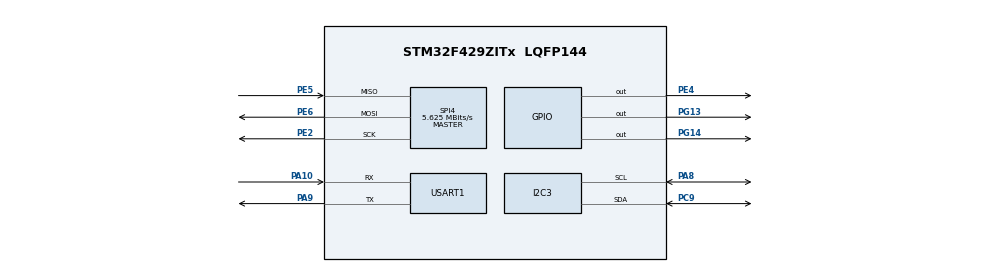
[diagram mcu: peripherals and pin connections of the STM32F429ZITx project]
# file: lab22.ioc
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I2C3.I2C_Mode=I2C_Fast
Mcu.Family=STM32F4
Mcu.Name=STM32F429ZITx
Mcu.Package=LQFP144
NVIC.PriorityGroup=NVIC_PRIORITYGROUP_4
PA10.Mode=Asynchronous
PA10.Signal=USART1_RX
PA8.Mode=I2C
PA8.Signal=I2C3_SCL
PA9.Mode=Asynchronous
PA9.Signal=USART1_TX
PC9.Mode=I2C
PC9.Signal=I2C3_SDA
PE2.Mode=Full_Duplex_Master
PE2.Signal=SPI4_SCK
PE4.Signal=GPIO_Output
PE5.Mode=Full_Duplex_Master
PE5.Signal=SPI4_MISO
PE6.Mode=Full_Duplex_Master
PE6.Signal=SPI4_MOSI
PG13.Signal=GPIO_Output
PG14.Signal=GPIO_Output
PH0/OSC_IN.Mode=HSE-External-Oscillator
PH0/OSC_IN.Signal=RCC_OSC_IN
PH1/OSC_OUT.Mode=HSE-External-Oscillator
PH1/OSC_OUT.Signal=RCC_OSC_OUT
ProjectManager.HeapSize=0x200
ProjectManager.StackSize=0x400
ProjectManager.TargetToolchain=STM32CubeIDE
RCC.48MHZClocksFreq_Value=90000000
RCC.AHBFreq_Value=180000000
RCC.APB1CLKDivider=RCC_HCLK_DIV4
RCC.APB1Freq_Value=45000000
RCC.APB1TimFreq_Value=90000000
RCC.APB2CLKDivider=RCC_HCLK_DIV2
RCC.APB2Freq_Value=90000000
RCC.APB2TimFreq_Value=180000000
RCC.CortexFreq_Value=180000000
RCC.HCLKFreq_Value=180000000
RCC.HSE_VALUE=25000000
RCC.HSI_VALUE=16000000
RCC.LSE_VALUE=32768
RCC.PLLM=15
RCC.PLLN=216
RCC.PLLSourceVirtual=RCC_PLLSOURCE_HSE
RCC.SYSCLKFreq_VALUE=180000000
RCC.SYSCLKSource=RCC_SYSCLKSOURCE_PLLCLK
RCC.VCOOutputFreq_Value=360000000
SPI4.BaudRatePrescaler=SPI_BAUDRATEPRESCALER_16
SPI4.CalculateBaudRate=5.625 MBits/s
SPI4.Direction=SPI_DIRECTION_2LINES
SPI4.Mode=SPI_MODE_MASTER
SPI4.VirtualType=VM_MASTER
USART1.VirtualMode=VM_ASYNC
board=custom

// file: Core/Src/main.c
/* USER CODE BEGIN Header */
/**
 ******************************************************************************
 * @file           : main.c
 * @brief          : Main program body
 ******************************************************************************
 * @attention
 *
 * Copyright (c) 2025 STMicroelectronics.
 * All rights reserved.
 *
 * This software is licensed under terms that can be found in the LICENSE file
 * in the root directory of this software component.
 * If no LICENSE file comes with this software, it is provided AS-IS.
 *
 ******************************************************************************
 */
/* USER CODE END Header */
#include "main.h"

/* USER CODE BEGIN Includes */
#include "tm_stm32f4_mfrc522.h"
#include "stdio.h"
#include "string.h"
#include "SH1106.h"
#include "fonts.h"
/* USER CODE END Includes */

/* USER CODE BEGIN PTD */
struct Time {
	uint8_t sec;
	uint8_t min;
	uint8_t hour;
	uint8_t weekday;
	uint8_t day;
	uint8_t month;
	uint8_t year;
};

/* USER CODE END PTD */

I2C_HandleTypeDef hi2c3;

SPI_HandleTypeDef hspi4;

UART_HandleTypeDef huart1;

void SystemClock_Config(void);
static void MX_GPIO_Init(void);
static void MX_SPI4_Init(void);
static void MX_USART1_UART_Init(void);
static void MX_I2C3_Init(void);

// Hàm chuyển đổi giá trị BCD sang số thập phân
uint8_t bcdToDec(uint8_t bcd) {
	return ((bcd >> 4) * 10) + (bcd & 0x0F);
}

// Hàm chuyển đổi số thập phân sang giá trị BCD
uint8_t decToBcd(uint8_t dec) {
	return ((dec / 10) << 4) | (dec % 10);
}

void SetDS1307(int sec, int min, int hour, int day, int month, int year,
		int weekday) {
	struct Time Set_time;
	Set_time.sec = decToBcd(sec);   // Chuyển đổi sang BCD
	Set_time.min = decToBcd(min);   // Chuyển đổi sang BCD
	Set_time.hour = decToBcd(hour); // Chuyển đổi sang BCD
	Set_time.day = decToBcd(day);   // Chuyển đổi sang BCD
	Set_time.month = decToBcd(month); // Chuyển đổi sang BCD
	Set_time.year = decToBcd(year); // Chuyển đổi sang BCD
	Set_time.weekday = decToBcd(weekday); // Chuyển đổi sang BCD
	//write time to DS1307
	HAL_I2C_Mem_Write(&hi2c3, 0xD0, 0, 1, (uint8_t*) &Set_time, 7, 1000);
}

void GetDS1307_1(char buff[]) {
	struct Time Get_Time;
	//read time back
	HAL_I2C_Mem_Read(&hi2c3, 0xD1, 0, 1, (uint8_t*) &Get_Time, 7, 1000);

	uint8_t sec_dec = bcdToDec(Get_Time.sec);
	uint8_t min_dec = bcdToDec(Get_Time.min);
	uint8_t hour_dec = bcdToDec(Get_Time.hour);

	sprintf(buff, "%02d:%02d:%02d", hour_dec, min_dec, sec_dec);
}

void GetDS1307_2(char buff[]) {
	struct Time Get_Time;
	//read time back
	HAL_I2C_Mem_Read(&hi2c3, 0xD1, 0, 1, (uint8_t*) &Get_Time, 7, 1000);

	uint8_t weekday_dec = bcdToDec(Get_Time.weekday);
	uint8_t day_dec = bcdToDec(Get_Time.day);
	uint8_t month_dec = bcdToDec(Get_Time.month);
	uint8_t year_dec = bcdToDec(Get_Time.year);

	sprintf(buff, "%01d-%02d/%02d/%02d\n", weekday_dec, day_dec, month_dec,
			year_dec);
}

/* USER CODE END 0 */

int main(void) {

	/* MCU Configuration--------------------------------------------------------*/

	/* Reset of all peripherals, Initializes the Flash interface and the Systick. */
	HAL_Init();

	/* Configure the system clock */
	SystemClock_Config();

	/* Initialize all configured peripherals */
	MX_GPIO_Init();
	MX_SPI4_Init();
	MX_USART1_UART_Init();
	MX_I2C3_Init();

	/* USER CODE BEGIN 2 */
	TM_MFRC522_Init();
	char buf[100];
	SH1106_Init();
	sprintf(buf, "%s", "CardID:");
	SH1106_GotoXY(12, 0); // goto 10, 10
	SH1106_Puts(buf, &Font_11x18, 1);
	SH1106_UpdateScreen(); // update screen
	HAL_Delay(1000);
	char buff[30];
	SetDS1307(0, 15, 15, 19, 4, 25, 7);
	/* USER CODE END 2 */

	/* Create the thread(s) */
	/* definition and creation of defaultTask */
	osThreadDef(defaultTask, StartDefaultTask, osPriorityNormal, 0, 4096);
	defaultTaskHandle = osThreadCreate(osThread(defaultTask), NULL);

	/* Start scheduler */
	osKernelStart();

	/* We should never get here as control is now taken by the scheduler */

	/* Infinite loop */
	while (1) {

		/* USER CODE BEGIN 3 */
		uint8_t CardID[5];
		HAL_Delay(100);
		if (TM_MFRC522_Check(CardID) == MI_OK) {
			SH1106_GotoXY(35, 20);
			GetDS1307_1(buff);
			HAL_UART_Transmit(&huart1, (const uint8_t*) buff, strlen(buff),
					1000);
			SH1106_Puts(buff, &Font_7x10, 1);
			SH1106_GotoXY(10, 32);
			GetDS1307_2(buff);
			HAL_UART_Transmit(&huart1, (const uint8_t*) buff, strlen(buff),
					1000);
			SH1106_Puts(buff, &Font_7x10, 1);
			sprintf(buf, "%02X%02X%02X%02X%02X\n", CardID[0], CardID[1],
					CardID[2], CardID[3], CardID[4]);
			SH1106_GotoXY(10, 45);
			SH1106_Puts(buf, &Font_11x18, 1);
			SH1106_UpdateScreen();
			HAL_UART_Transmit(&huart1, (const uint8_t*) buf, strlen(buf), 2);
			HAL_Delay(200);
		} else {
			SH1106_GotoXY(35, 20);
			GetDS1307_1(buff);
			SH1106_Puts(buff, &Font_7x10, 1);
			HAL_UART_Transmit(&huart1, (const uint8_t*) buff, strlen(buff),
					1000);
			SH1106_GotoXY(10, 32);
			SH1106_UpdateScreen();
		}
		/* USER CODE END 3 */
	}
}

void SystemClock_Config(void) {
	RCC_OscInitTypeDef RCC_OscInitStruct = { 0 };
	RCC_ClkInitTypeDef RCC_ClkInitStruct = { 0 };

	/** Configure the main internal regulator output voltage
	 */
	__HAL_RCC_PWR_CLK_ENABLE();
	__HAL_PWR_VOLTAGESCALING_CONFIG(PWR_REGULATOR_VOLTAGE_SCALE3);

	/** Initializes the RCC Oscillators according to the specified parameters
	 * in the RCC_OscInitTypeDef structure.
	 */
	RCC_OscInitStruct.OscillatorType = RCC_OSCILLATORTYPE_HSE;
	RCC_OscInitStruct.HSEState = RCC_HSE_ON;
	RCC_OscInitStruct.PLL.PLLState = RCC_PLL_ON;
	RCC_OscInitStruct.PLL.PLLSource = RCC_PLLSOURCE_HSE;
	RCC_OscInitStruct.PLL.PLLM = 4;
	RCC_OscInitStruct.PLL.PLLN = 72;
	RCC_OscInitStruct.PLL.PLLP = RCC_PLLP_DIV2;
	RCC_OscInitStruct.PLL.PLLQ = 3;
	if (HAL_RCC_OscConfig(&RCC_OscInitStruct) != HAL_OK) {
		Error_Handler();
	}

	/** Initializes the CPU, AHB and APB buses clocks
	 */
	RCC_ClkInitStruct.ClockType = RCC_CLOCKTYPE_HCLK | RCC_CLOCKTYPE_SYSCLK
			| RCC_CLOCKTYPE_PCLK1 | RCC_CLOCKTYPE_PCLK2;
	RCC_ClkInitStruct.SYSCLKSource = RCC_SYSCLKSOURCE_PLLCLK;
	RCC_ClkInitStruct.AHBCLKDivider = RCC_SYSCLK_DIV1;
	RCC_ClkInitStruct.APB1CLKDivider = RCC_HCLK_DIV2;
	RCC_ClkInitStruct.APB2CLKDivider = RCC_HCLK_DIV1;

	if (HAL_RCC_ClockConfig(&RCC_ClkInitStruct, FLASH_LATENCY_2) != HAL_OK) {
		Error_Handler();
	}
}

static void MX_CRC_Init(void) {

	hcrc.Instance = CRC;
	if (HAL_CRC_Init(&hcrc) != HAL_OK) {
		Error_Handler();
	}

}

static void MX_DMA2D_Init(void) {

	hdma2d.Instance = DMA2D;
	hdma2d.Init.Mode = DMA2D_M2M;
	hdma2d.Init.ColorMode = DMA2D_OUTPUT_ARGB8888;
	hdma2d.Init.OutputOffset = 0;
	hdma2d.LayerCfg[1].InputOffset = 0;
	hdma2d.LayerCfg[1].InputColorMode = DMA2D_INPUT_ARGB8888;
	hdma2d.LayerCfg[1].AlphaMode = DMA2D_NO_MODIF_ALPHA;
	hdma2d.LayerCfg[1].InputAlpha = 0;
	if (HAL_DMA2D_Init(&hdma2d) != HAL_OK) {
		Error_Handler();
	}
	if (HAL_DMA2D_ConfigLayer(&hdma2d, 1) != HAL_OK) {
		Error_Handler();
	}

}

static void MX_I2C3_Init(void) {

	hi2c3.Instance = I2C3;
	hi2c3.Init.ClockSpeed = 400000;
	hi2c3.Init.DutyCycle = I2C_DUTYCYCLE_2;
	hi2c3.Init.OwnAddress1 = 0;
	hi2c3.Init.AddressingMode = I2C_ADDRESSINGMODE_7BIT;
	hi2c3.Init.DualAddressMode = I2C_DUALADDRESS_DISABLE;
	hi2c3.Init.OwnAddress2 = 0;
	hi2c3.Init.GeneralCallMode = I2C_GENERALCALL_DISABLE;
	hi2c3.Init.NoStretchMode = I2C_NOSTRETCH_DISABLE;
	if (HAL_I2C_Init(&hi2c3) != HAL_OK) {
		Error_Handler();
	}

	/** Configure Analogue filter
	 */
	if (HAL_I2CEx_ConfigAnalogFilter(&hi2c3, I2C_ANALOGFILTER_ENABLE)
			!= HAL_OK) {
		Error_Handler();
	}

	/** Configure Digital filter
	 */
	if (HAL_I2CEx_ConfigDigitalFilter(&hi2c3, 0) != HAL_OK) {
		Error_Handler();
	}

}

static void MX_LTDC_Init(void) {

	LTDC_LayerCfgTypeDef pLayerCfg = { 0 };

	hltdc.Instance = LTDC;
	hltdc.Init.HSPolarity = LTDC_HSPOLARITY_AL;
	hltdc.Init.VSPolarity = LTDC_VSPOLARITY_AL;
	hltdc.Init.DEPolarity = LTDC_DEPOLARITY_AL;
	hltdc.Init.PCPolarity = LTDC_PCPOLARITY_IPC;
	hltdc.Init.HorizontalSync = 9;
	hltdc.Init.VerticalSync = 1;
	hltdc.Init.AccumulatedHBP = 29;
	hltdc.Init.AccumulatedVBP = 3;
	hltdc.Init.AccumulatedActiveW = 269;
	hltdc.Init.AccumulatedActiveH = 323;
	hltdc.Init.TotalWidth = 279;
	hltdc.Init.TotalHeigh = 327;
	hltdc.Init.Backcolor.Blue = 0;
	hltdc.Init.Backcolor.Green = 0;
	hltdc.Init.Backcolor.Red = 0;
	if (HAL_LTDC_Init(&hltdc) != HAL_OK) {
		Error_Handler();
	}
	pLayerCfg.WindowX0 = 0;
	pLayerCfg.WindowX1 = 240;
	pLayerCfg.WindowY0 = 0;
	pLayerCfg.WindowY1 = 320;
	pLayerCfg.PixelFormat = LTDC_PIXEL_FORMAT_RGB565;
	pLayerCfg.Alpha = 255;
	pLayerCfg.Alpha0 = 0;
	pLayerCfg.BlendingFactor1 = LTDC_BLENDING_FACTOR1_PAxCA;
	pLayerCfg.BlendingFactor2 = LTDC_BLENDING_FACTOR2_PAxCA;
	pLayerCfg.FBStartAdress = 0xD0000000;
	pLayerCfg.ImageWidth = 240;
	pLayerCfg.ImageHeight = 320;
	pLayerCfg.Backcolor.Blue = 0;
	pLayerCfg.Backcolor.Green = 0;
	pLayerCfg.Backcolor.Red = 0;
	if (HAL_LTDC_ConfigLayer(&hltdc, &pLayerCfg, 0) != HAL_OK) {
		Error_Handler();
	}

}

static void MX_SPI4_Init(void) {

	/* SPI4 parameter configuration*/
	hspi4.Instance = SPI4;
	hspi4.Init.Mode = SPI_MODE_MASTER;
	hspi4.Init.Direction = SPI_DIRECTION_2LINES;
	hspi4.Init.DataSize = SPI_DATASIZE_8BIT;
	hspi4.Init.CLKPolarity = SPI_POLARITY_LOW;
	hspi4.Init.CLKPhase = SPI_PHASE_1EDGE;
	hspi4.Init.NSS = SPI_NSS_SOFT;
	hspi4.Init.BaudRatePrescaler = SPI_BAUDRATEPRESCALER_16;
	hspi4.Init.FirstBit = SPI_FIRSTBIT_MSB;
	hspi4.Init.TIMode = SPI_TIMODE_DISABLE;
	hspi4.Init.CRCCalculation = SPI_CRCCALCULATION_DISABLE;
	hspi4.Init.CRCPolynomial = 10;
	if (HAL_SPI_Init(&hspi4) != HAL_OK) {
		Error_Handler();
	}

}

static void MX_SPI5_Init(void) {

	/* SPI5 parameter configuration*/
	hspi5.Instance = SPI5;
	hspi5.Init.Mode = SPI_MODE_MASTER;
	hspi5.Init.Direction = SPI_DIRECTION_2LINES;
	hspi5.Init.DataSize = SPI_DATASIZE_8BIT;
	hspi5.Init.CLKPolarity = SPI_POLARITY_LOW;
	hspi5.Init.CLKPhase = SPI_PHASE_1EDGE;
	hspi5.Init.NSS = SPI_NSS_SOFT;
	hspi5.Init.BaudRatePrescaler = SPI_BAUDRATEPRESCALER_16;
	hspi5.Init.FirstBit = SPI_FIRSTBIT_MSB;
	hspi5.Init.TIMode = SPI_TIMODE_DISABLE;
	hspi5.Init.CRCCalculation = SPI_CRCCALCULATION_DISABLE;
	hspi5.Init.CRCPolynomial = 10;
	if (HAL_SPI_Init(&hspi5) != HAL_OK) {
		Error_Handler();
	}

}

static void MX_TIM1_Init(void) {

	TIM_ClockConfigTypeDef sClockSourceConfig = { 0 };
	TIM_MasterConfigTypeDef sMasterConfig = { 0 };

	htim1.Instance = TIM1;
	htim1.Init.Prescaler = 0;
	htim1.Init.CounterMode = TIM_COUNTERMODE_UP;
	htim1.Init.Period = 65535;
	htim1.Init.ClockDivision = TIM_CLOCKDIVISION_DIV1;
	htim1.Init.RepetitionCounter = 0;
	htim1.Init.AutoReloadPreload = TIM_AUTORELOAD_PRELOAD_DISABLE;
	if (HAL_TIM_Base_Init(&htim1) != HAL_OK) {
		Error_Handler();
	}
	sClockSourceConfig.ClockSource = TIM_CLOCKSOURCE_INTERNAL;
	if (HAL_TIM_ConfigClockSource(&htim1, &sClockSourceConfig) != HAL_OK) {
		Error_Handler();
	}
	sMasterConfig.MasterOutputTrigger = TIM_TRGO_RESET;
	sMasterConfig.MasterSlaveMode = TIM_MASTERSLAVEMODE_DISABLE;
	if (HAL_TIMEx_MasterConfigSynchronization(&htim1, &sMasterConfig)
			!= HAL_OK) {
		Error_Handler();
	}

}

static void MX_USART1_UART_Init(void) {

	huart1.Instance = USART1;
	huart1.Init.BaudRate = 115200;
	huart1.Init.WordLength = UART_WORDLENGTH_8B;
	huart1.Init.StopBits = UART_STOPBITS_1;
	huart1.Init.Parity = UART_PARITY_NONE;
	huart1.Init.Mode = UART_MODE_TX_RX;
	huart1.Init.HwFlowCtl = UART_HWCONTROL_NONE;
	huart1.Init.OverSampling = UART_OVERSAMPLING_16;
	if (HAL_UART_Init(&huart1) != HAL_OK) {
		Error_Handler();
	}

}

/* FMC initialization function */
static void MX_FMC_Init(void) {

	FMC_SDRAM_TimingTypeDef SdramTiming = { 0 };

	/** Perform the SDRAM1 memory initialization sequence
	 */
	hsdram1.Instance = FMC_SDRAM_DEVICE;
	/* hsdram1.Init */
	hsdram1.Init.SDBank = FMC_SDRAM_BANK2;
	hsdram1.Init.ColumnBitsNumber = FMC_SDRAM_COLUMN_BITS_NUM_8;
	hsdram1.Init.RowBitsNumber = FMC_SDRAM_ROW_BITS_NUM_12;
	hsdram1.Init.MemoryDataWidth = FMC_SDRAM_MEM_BUS_WIDTH_16;
	hsdram1.Init.InternalBankNumber = FMC_SDRAM_INTERN_BANKS_NUM_4;
	hsdram1.Init.CASLatency = FMC_SDRAM_CAS_LATENCY_3;
	hsdram1.Init.WriteProtection = FMC_SDRAM_WRITE_PROTECTION_DISABLE;
	hsdram1.Init.SDClockPeriod = FMC_SDRAM_CLOCK_PERIOD_2;
	hsdram1.Init.ReadBurst = FMC_SDRAM_RBURST_DISABLE;
	hsdram1.Init.ReadPipeDelay = FMC_SDRAM_RPIPE_DELAY_1;
	/* SdramTiming */
	SdramTiming.LoadToActiveDelay = 2;
	SdramTiming.ExitSelfRefreshDelay = 7;
	SdramTiming.SelfRefreshTime = 4;
	SdramTiming.RowCycleDelay = 7;
	SdramTiming.WriteRecoveryTime = 3;
	SdramTiming.RPDelay = 2;
	SdramTiming.RCDDelay = 2;

	if (HAL_SDRAM_Init(&hsdram1, &SdramTiming) != HAL_OK) {
		Error_Handler();
	}

}

static void MX_GPIO_Init(void) {
	GPIO_InitTypeDef GPIO_InitStruct = { 0 };

	/* GPIO Ports Clock Enable */
	__HAL_RCC_GPIOE_CLK_ENABLE();
	__HAL_RCC_GPIOC_CLK_ENABLE();
	__HAL_RCC_GPIOF_CLK_ENABLE();
	__HAL_RCC_GPIOH_CLK_ENABLE();
	__HAL_RCC_GPIOA_CLK_ENABLE();
	__HAL_RCC_GPIOB_CLK_ENABLE();
	__HAL_RCC_GPIOG_CLK_ENABLE();
	__HAL_RCC_GPIOD_CLK_ENABLE();

	/*Configure GPIO pin Output Level */
	HAL_GPIO_WritePin(GPIOE, GPIO_PIN_4, GPIO_PIN_RESET);

	/*Configure GPIO pin Output Level */
	HAL_GPIO_WritePin(GPIOC, NCS_MEMS_SPI_Pin | CSX_Pin | OTG_FS_PSO_Pin,
			GPIO_PIN_RESET);

	/*Configure GPIO pin Output Level */
	HAL_GPIO_WritePin(ACP_RST_GPIO_Port, ACP_RST_Pin, GPIO_PIN_RESET);

	/*Configure GPIO pin Output Level */
	HAL_GPIO_WritePin(GPIOD, RDX_Pin | WRX_DCX_Pin, GPIO_PIN_RESET);

	/*Configure GPIO pin Output Level */
	HAL_GPIO_WritePin(GPIOG, LD3_Pin | LD4_Pin, GPIO_PIN_RESET);

	/*Configure GPIO pin : PE4 */
	GPIO_InitStruct.Pin = GPIO_PIN_4;
	GPIO_InitStruct.Mode = GPIO_MODE_OUTPUT_PP;
	GPIO_InitStruct.Pull = GPIO_NOPULL;
	GPIO_InitStruct.Speed = GPIO_SPEED_FREQ_LOW;
	HAL_GPIO_Init(GPIOE, &GPIO_InitStruct);

	/*Configure GPIO pins : NCS_MEMS_SPI_Pin CSX_Pin OTG_FS_PSO_Pin */
	GPIO_InitStruct.Pin = NCS_MEMS_SPI_Pin | CSX_Pin | OTG_FS_PSO_Pin;
	GPIO_InitStruct.Mode = GPIO_MODE_OUTPUT_PP;
	GPIO_InitStruct.Pull = GPIO_NOPULL;
	GPIO_InitStruct.Speed = GPIO_SPEED_FREQ_LOW;
	HAL_GPIO_Init(GPIOC, &GPIO_InitStruct);

	/*Configure GPIO pins : B1_Pin MEMS_INT1_Pin MEMS_INT2_Pin TP_INT1_Pin */
	GPIO_InitStruct.Pin = B1_Pin | MEMS_INT1_Pin | MEMS_INT2_Pin | TP_INT1_Pin;
	GPIO_InitStruct.Mode = GPIO_MODE_EVT_RISING;
	GPIO_InitStruct.Pull = GPIO_NOPULL;
	HAL_GPIO_Init(GPIOA, &GPIO_InitStruct);

	/*Configure GPIO pin : ACP_RST_Pin */
	GPIO_InitStruct.Pin = ACP_RST_Pin;
	GPIO_InitStruct.Mode = GPIO_MODE_OUTPUT_PP;
	GPIO_InitStruct.Pull = GPIO_NOPULL;
	GPIO_InitStruct.Speed = GPIO_SPEED_FREQ_LOW;
	HAL_GPIO_Init(ACP_RST_GPIO_Port, &GPIO_InitStruct);

	/*Configure GPIO pin : OTG_FS_OC_Pin */
	GPIO_InitStruct.Pin = OTG_FS_OC_Pin;
	GPIO_InitStruct.Mode = GPIO_MODE_EVT_RISING;
	GPIO_InitStruct.Pull = GPIO_NOPULL;
	HAL_GPIO_Init(OTG_FS_OC_GPIO_Port, &GPIO_InitStruct);

	/*Configure GPIO pin : BOOT1_Pin */
	GPIO_InitStruct.Pin = BOOT1_Pin;
	GPIO_InitStruct.Mode = GPIO_MODE_INPUT;
	GPIO_InitStruct.Pull = GPIO_NOPULL;
	HAL_GPIO_Init(BOOT1_GPIO_Port, &GPIO_InitStruct);

	/*Configure GPIO pin : TE_Pin */
	GPIO_InitStruct.Pin = TE_Pin;
	GPIO_InitStruct.Mode = GPIO_MODE_INPUT;
	GPIO_InitStruct.Pull = GPIO_NOPULL;
	HAL_GPIO_Init(TE_GPIO_Port, &GPIO_InitStruct);

	/*Configure GPIO pins : RDX_Pin WRX_DCX_Pin */
	GPIO_InitStruct.Pin = RDX_Pin | WRX_DCX_Pin;
	GPIO_InitStruct.Mode = GPIO_MODE_OUTPUT_PP;
	GPIO_InitStruct.Pull = GPIO_NOPULL;
	GPIO_InitStruct.Speed = GPIO_SPEED_FREQ_LOW;
	HAL_GPIO_Init(GPIOD, &GPIO_InitStruct);

	/*Configure GPIO pins : LD3_Pin LD4_Pin */
	GPIO_InitStruct.Pin = LD3_Pin | LD4_Pin;
	GPIO_InitStruct.Mode = GPIO_MODE_OUTPUT_PP;
	GPIO_InitStruct.Pull = GPIO_NOPULL;
	GPIO_InitStruct.Speed = GPIO_SPEED_FREQ_LOW;
	HAL_GPIO_Init(GPIOG, &GPIO_InitStruct);

}

void StartDefaultTask(void const *argument) {
	/* init code for USB_HOST */
	MX_USB_HOST_Init();
	for (;;) {
		osDelay(1);
	}
}

void HAL_TIM_PeriodElapsedCallback(TIM_HandleTypeDef *htim) {
	if (htim->Instance == TIM6) {
		HAL_IncTick();
	}
}

void Error_Handler(void) {
	__disable_irq();
	while (1) {
	}
}
